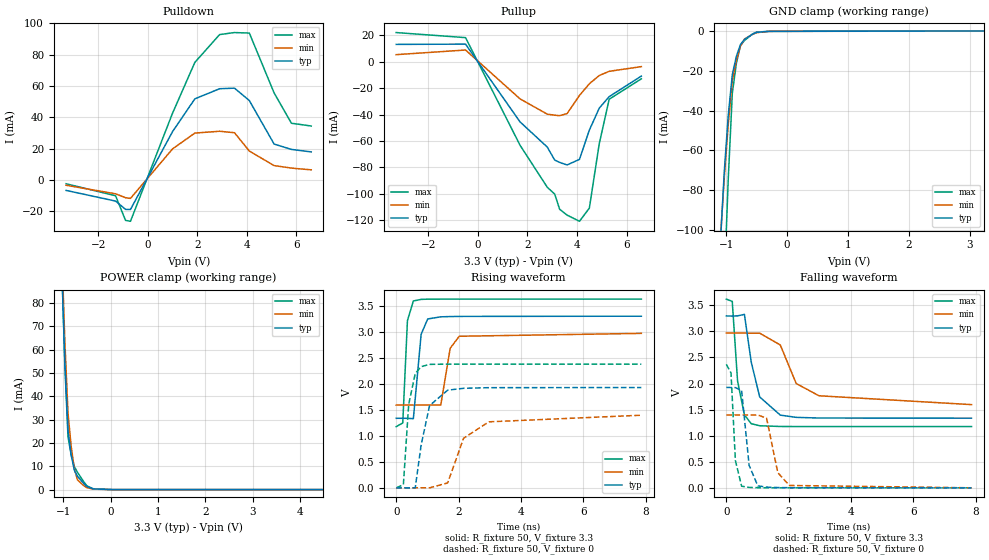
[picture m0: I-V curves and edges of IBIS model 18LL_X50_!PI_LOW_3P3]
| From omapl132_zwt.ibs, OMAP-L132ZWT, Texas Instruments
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|   Model Cell 18LL_X50_!PI_LOW_3P3
|BC1833DV40CTPBFZ_!PI_LOW_3P3
[Model]   18LL_X50_!PI_LOW_3P3
Model_type   I/O
Polarity   Non-Inverting
Enable   Active-Low
Vinl =  0.8V
Vinh =  2V
Cref =  15pF
Rref =  100.00M
Vref =  0V
Vmeas =  1.65
C_comp   1.943144p   1.721292p   2.064363p
[Model Spec]
Vinl   0.8V   0.8V   0.8V
Vinh   2V   2V   2V
[Temperature Range]   25   125   -40
[Voltage Range]   3.3   2.97   3.63
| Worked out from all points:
|   slope of the pulldown table from 0 to 0.495 V, typ, clamps not added: 31.5 ohm
|   slope of the pullup table from 0 to 0.495 V, typ, clamps not added: 35.2 ohm
|   GND clamp passes 1 mA (typ) near -0.54 V on its own axis
|   POWER clamp passes 1 mA (typ) near -0.47 V on its own axis
|   rising waveform, R_fixture 50, V_fixture 3.3: 20-80 % time 145ps typ, 209ps min, 98.8ps max; typ from 1.34 V to 3.3 V
|   rising waveform, R_fixture 50, V_fixture 0: 20-80 % time 316ps typ, 692ps min, 182ps max; typ from 0 V to 1.93 V
|   falling waveform, R_fixture 50, V_fixture 3.3: 20-80 % time 386ps typ, 780ps min, 206ps max; typ from 3.3 V to 1.34 V
|   falling waveform, R_fixture 50, V_fixture 0: 20-80 % time 167ps typ, 249ps min, 117ps max; typ from 1.93 V to 0 V
[POWER_clamp]
|   voltage   I(typ)   I(min)   I(max)
-3.3V     2.432A     2.868A     2.62A
-1.033V   95.19mA    103.3mA    97.04mA
-966.7mV  55.03mA    63.43mA    53.21mA
-900mV    25.31mA    32.8mA     22.52mA
-833.3mV  14.85mA    18.49mA    14.91mA
-766.7mV  8.322mA    8.944mA    9.876mA
-700mV    5.715mA    4.176mA    7.414mA
-566.7mV  2.626mA    1.656mA    3.321mA
-500mV    1.33mA     834.8uA    1.583mA
-366.7mV  291uA      194.1uA    374.2uA
33.33mV   0A         0A         0A
6.6V      0A         0A         0A
[Pulldown]
|   voltage   I(typ)   I(min)   I(max)
-3.3V     -6.708mA   -3.419mA   -2.439mA
-1.3V     -13.52mA   -8.874mA   -10.14mA
-900mV    -18.83mA   -11.38mA   -25.87mA
-700mV    -18.88mA   -11.81mA   -26.45mA
1V        30.91mA    19.84mA    42.7mA
1.9V      51.83mA    29.94mA    75.14mA
2.9V      58.3mA     31.12mA    92.92mA
3.5V      58.67mA    30.17mA    94.2mA
4.1V      50.73mA    18.46mA    93.88mA
5.1V      22.94mA    9.149mA    55.64mA
5.8V      19.5mA     7.56mA     36.23mA
6.6V      17.91mA    6.449mA    34.47mA
[Pullup]
|   voltage   I(typ)   I(min)   I(max)
-3.3V     13.07mA    5.31mA     22.02mA
-500mV    13.27mA    8.819mA    18.19mA
1.7V      -45.56mA   -28.16mA   -63.21mA
2.8V      -64.62mA   -39.71mA   -95.04mA
3.1V      -74.46mA   -40.51mA   -100.2mA
3.3V      -76.24mA   -40.86mA   -111.7mA
3.6V      -78.17mA   -39.29mA   -116.1mA
4.1V      -73.95mA   -25.59mA   -120.8mA
4.5V      -51.77mA   -16.71mA   -110.8mA
4.9V      -35.15mA   -10.47mA   -62.03mA
5.3V      -26.46mA   -7.311mA   -28.43mA
6.6V      -10.91mA   -3.736mA   -12.96mA
[GND_clamp]
|   voltage   I(typ)   I(min)   I(max)
-3.3V     -2.048A    -1.805A    -3.667A
-1.1V     -108.6mA   -106.5mA   -191.4mA
-1.033V   -71.12mA   -74.04mA   -127.7mA
-966.7mV  -42.17mA   -46.83mA   -74.25mA
-900mV    -21.74mA   -24.88mA   -31.11mA
-833.3mV  -12.59mA   -14.47mA   -16.09mA
-766.7mV  -6.705mA   -7.468mA   -7.261mA
-700mV    -4.083mA   -3.88mA    -4.614mA
-566.7mV  -1.424mA   -1.483mA   -1.356mA
-500mV    -523uA     -696.9uA   -399.5uA
-300mV    -31.02uA   -34.87uA   -39.83uA
3.233V    153.5uA    98.21uA    245.7uA
[Ramp]
| variable   typ   min   max
dV/dt_f   1.21122/0.3842262n  0.8579963/0.7852123n   1.483519/0.2058375n
dV/dt_r   1.164343/0.3161229n  0.8458352/0.6948985n   1.433316/0.1819928n
R_load = 50
[Rising Waveform]
R_fixture = 50
V_fixture = 3.3
V_fixture_min = 2.97
V_fixture_max = 3.63
|   time   V(typ)   V(min)   V(max)
0s        1.336V     1.59V      1.176V
210ps     1.336V     1.59V      1.246V
360ps     1.336V     1.59V      3.213V
550ps     1.328V     1.59V      3.59V
800ps     2.951V     1.59V      3.62V
1.01ns    3.244V     1.59V      3.624V
1.43ns    3.285V     1.592V     3.625V
1.73ns    3.29V      2.681V     3.625V
2.02ns    3.293V     2.912V     3.625V
7.86ns    3.297V     2.967V     3.625V
[Rising Waveform]
R_fixture = 50
V_fixture = 0
V_fixture_min = 0
V_fixture_max = 0
|   time   V(typ)   V(min)   V(max)
0s        -341.4nV   124.8nV    -636.8nV
230ps     -95.89nV   443nV      61.57mV
400ps     -439.1uV   -142.1nV   1.601V
610ps     714.5uV    -30.96nV   2.195V
800ps     825.8mV    110.3nV    2.328V
1.07ns    1.58V      -27.88uV   2.372V
1.65ns    1.876V     93.73mV    2.376V
2.16ns    1.912V     952.7mV    2.376V
2.97ns    1.924V     1.268V     2.376V
7.86ns    1.927V     1.395V     2.375V
[Falling Waveform]
R_fixture = 50
V_fixture = 3.3
V_fixture_min = 2.97
V_fixture_max = 3.63
|   time   V(typ)   V(min)   V(max)
0s        3.297V     2.968V     3.619V
190ps     3.294V     2.968V     3.576V
360ps     3.298V     2.968V     2.048V
580ps     3.326V     2.968V     1.399V
800ps     2.407V     2.966V     1.23V
1.07ns    1.743V     2.966V     1.191V
1.73ns    1.395V     2.74V      1.177V
2.24ns    1.352V     2.001V     1.176V
2.97ns    1.339V     1.766V     1.176V
7.86ns    1.336V     1.596V     1.176V
[Falling Waveform]
R_fixture = 50
V_fixture = 0
V_fixture_min = 0
V_fixture_max = 0
|   time   V(typ)   V(min)   V(max)
0s        1.927V     1.398V     2.368V
150ps     1.924V     1.398V     2.203V
290ps     1.922V     1.398V     525.8mV
490ps     1.869V     1.398V     31.63mV
730ps     431.5mV    1.397V     8.862mV
1.01ns    38.74mV    1.396V     2.736mV
1.29ns    14.06mV    1.338V     1.025mV
1.65ns    6.316mV    291.1mV    367.1uV
2.02ns    3.188mV    46.07mV    150.7uV
7.86ns    7.675uV    987.9uV    132.6nV
